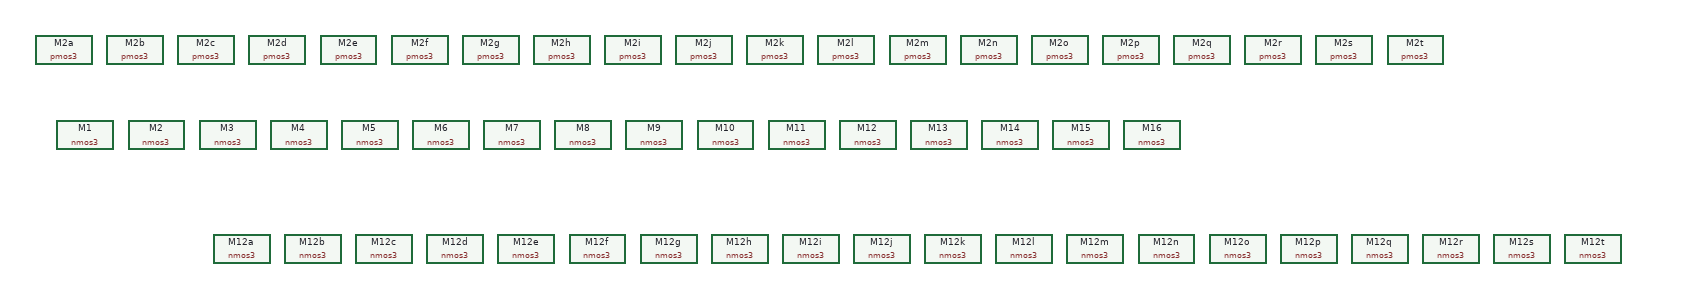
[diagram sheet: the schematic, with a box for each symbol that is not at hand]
v {xschem version=2.9.9 file_version=1.2 }
G {}
K {}
V {}
S {}
E {}
C {madvlsi/pmos3.sym} 580 -1460 1 0 {name=M2a
L=0.5
W=3
body=VDD
nf=1
mult=1
ad="'int((nf+1)/2) * W/nf * 0.29'" 
pd="'2*int((nf+1)/2) * (W/nf + 0.29)'"
as="'int((nf+2)/2) * W/nf * 0.29'" 
ps="'2*int((nf+2)/2) * (W/nf + 0.29)'"
nrd="'0.29 / W'" nrs="'0.29 / W'"
sa=0 sb=0 sd=0
model=pfet_01v8
spiceprefix=X
}
C {madvlsi/nmos3.sym} 830 -1180 1 0 {name=M12a
L=0.5
W=3
body=GND
nf=1
mult=1
ad="'int((nf+1)/2) * W/nf * 0.29'" 
pd="'2*int((nf+1)/2) * (W/nf + 0.29)'"
as="'int((nf+2)/2) * W/nf * 0.29'" 
ps="'2*int((nf+2)/2) * (W/nf + 0.29)'"
nrd="'0.29 / W'" nrs="'0.29 / W'"
sa=0 sb=0 sd=0
model=nfet_01v8
spiceprefix=X
}
C {madvlsi/nmos3.sym} 930 -1180 1 0 {name=M12b
L=0.5
W=3
body=GND
nf=1
mult=1
ad="'int((nf+1)/2) * W/nf * 0.29'" 
pd="'2*int((nf+1)/2) * (W/nf + 0.29)'"
as="'int((nf+2)/2) * W/nf * 0.29'" 
ps="'2*int((nf+2)/2) * (W/nf + 0.29)'"
nrd="'0.29 / W'" nrs="'0.29 / W'"
sa=0 sb=0 sd=0
model=nfet_01v8
spiceprefix=X
}
C {madvlsi/nmos3.sym} 1030 -1180 1 0 {name=M12c
L=0.5
W=3
body=GND
nf=1
mult=1
ad="'int((nf+1)/2) * W/nf * 0.29'" 
pd="'2*int((nf+1)/2) * (W/nf + 0.29)'"
as="'int((nf+2)/2) * W/nf * 0.29'" 
ps="'2*int((nf+2)/2) * (W/nf + 0.29)'"
nrd="'0.29 / W'" nrs="'0.29 / W'"
sa=0 sb=0 sd=0
model=nfet_01v8
spiceprefix=X
}
C {madvlsi/nmos3.sym} 1130 -1180 1 0 {name=M12d
L=0.5
W=3
body=GND
nf=1
mult=1
ad="'int((nf+1)/2) * W/nf * 0.29'" 
pd="'2*int((nf+1)/2) * (W/nf + 0.29)'"
as="'int((nf+2)/2) * W/nf * 0.29'" 
ps="'2*int((nf+2)/2) * (W/nf + 0.29)'"
nrd="'0.29 / W'" nrs="'0.29 / W'"
sa=0 sb=0 sd=0
model=nfet_01v8
spiceprefix=X
}
C {madvlsi/nmos3.sym} 1230 -1180 1 0 {name=M12e
L=0.5
W=3
body=GND
nf=1
mult=1
ad="'int((nf+1)/2) * W/nf * 0.29'" 
pd="'2*int((nf+1)/2) * (W/nf + 0.29)'"
as="'int((nf+2)/2) * W/nf * 0.29'" 
ps="'2*int((nf+2)/2) * (W/nf + 0.29)'"
nrd="'0.29 / W'" nrs="'0.29 / W'"
sa=0 sb=0 sd=0
model=nfet_01v8
spiceprefix=X
}
C {madvlsi/nmos3.sym} 1330 -1180 1 0 {name=M12f
L=0.5
W=3
body=GND
nf=1
mult=1
ad="'int((nf+1)/2) * W/nf * 0.29'" 
pd="'2*int((nf+1)/2) * (W/nf + 0.29)'"
as="'int((nf+2)/2) * W/nf * 0.29'" 
ps="'2*int((nf+2)/2) * (W/nf + 0.29)'"
nrd="'0.29 / W'" nrs="'0.29 / W'"
sa=0 sb=0 sd=0
model=nfet_01v8
spiceprefix=X
}
C {madvlsi/nmos3.sym} 1430 -1180 1 0 {name=M12g
L=0.5
W=3
body=GND
nf=1
mult=1
ad="'int((nf+1)/2) * W/nf * 0.29'" 
pd="'2*int((nf+1)/2) * (W/nf + 0.29)'"
as="'int((nf+2)/2) * W/nf * 0.29'" 
ps="'2*int((nf+2)/2) * (W/nf + 0.29)'"
nrd="'0.29 / W'" nrs="'0.29 / W'"
sa=0 sb=0 sd=0
model=nfet_01v8
spiceprefix=X
}
C {madvlsi/nmos3.sym} 1530 -1180 1 0 {name=M12h
L=0.5
W=3
body=GND
nf=1
mult=1
ad="'int((nf+1)/2) * W/nf * 0.29'" 
pd="'2*int((nf+1)/2) * (W/nf + 0.29)'"
as="'int((nf+2)/2) * W/nf * 0.29'" 
ps="'2*int((nf+2)/2) * (W/nf + 0.29)'"
nrd="'0.29 / W'" nrs="'0.29 / W'"
sa=0 sb=0 sd=0
model=nfet_01v8
spiceprefix=X
}
C {madvlsi/nmos3.sym} 1630 -1180 1 0 {name=M12i
L=0.5
W=3
body=GND
nf=1
mult=1
ad="'int((nf+1)/2) * W/nf * 0.29'" 
pd="'2*int((nf+1)/2) * (W/nf + 0.29)'"
as="'int((nf+2)/2) * W/nf * 0.29'" 
ps="'2*int((nf+2)/2) * (W/nf + 0.29)'"
nrd="'0.29 / W'" nrs="'0.29 / W'"
sa=0 sb=0 sd=0
model=nfet_01v8
spiceprefix=X
}
C {madvlsi/nmos3.sym} 1730 -1180 1 0 {name=M12j
L=0.5
W=3
body=GND
nf=1
mult=1
ad="'int((nf+1)/2) * W/nf * 0.29'" 
pd="'2*int((nf+1)/2) * (W/nf + 0.29)'"
as="'int((nf+2)/2) * W/nf * 0.29'" 
ps="'2*int((nf+2)/2) * (W/nf + 0.29)'"
nrd="'0.29 / W'" nrs="'0.29 / W'"
sa=0 sb=0 sd=0
model=nfet_01v8
spiceprefix=X
}
C {madvlsi/nmos3.sym} 1830 -1180 1 0 {name=M12k
L=0.5
W=3
body=GND
nf=1
mult=1
ad="'int((nf+1)/2) * W/nf * 0.29'" 
pd="'2*int((nf+1)/2) * (W/nf + 0.29)'"
as="'int((nf+2)/2) * W/nf * 0.29'" 
ps="'2*int((nf+2)/2) * (W/nf + 0.29)'"
nrd="'0.29 / W'" nrs="'0.29 / W'"
sa=0 sb=0 sd=0
model=nfet_01v8
spiceprefix=X
}
C {madvlsi/nmos3.sym} 1930 -1180 1 0 {name=M12l
L=0.5
W=3
body=GND
nf=1
mult=1
ad="'int((nf+1)/2) * W/nf * 0.29'" 
pd="'2*int((nf+1)/2) * (W/nf + 0.29)'"
as="'int((nf+2)/2) * W/nf * 0.29'" 
ps="'2*int((nf+2)/2) * (W/nf + 0.29)'"
nrd="'0.29 / W'" nrs="'0.29 / W'"
sa=0 sb=0 sd=0
model=nfet_01v8
spiceprefix=X
}
C {madvlsi/nmos3.sym} 2030 -1180 1 0 {name=M12m
L=0.5
W=3
body=GND
nf=1
mult=1
ad="'int((nf+1)/2) * W/nf * 0.29'" 
pd="'2*int((nf+1)/2) * (W/nf + 0.29)'"
as="'int((nf+2)/2) * W/nf * 0.29'" 
ps="'2*int((nf+2)/2) * (W/nf + 0.29)'"
nrd="'0.29 / W'" nrs="'0.29 / W'"
sa=0 sb=0 sd=0
model=nfet_01v8
spiceprefix=X
}
C {madvlsi/nmos3.sym} 2130 -1180 1 0 {name=M12n
L=0.5
W=3
body=GND
nf=1
mult=1
ad="'int((nf+1)/2) * W/nf * 0.29'" 
pd="'2*int((nf+1)/2) * (W/nf + 0.29)'"
as="'int((nf+2)/2) * W/nf * 0.29'" 
ps="'2*int((nf+2)/2) * (W/nf + 0.29)'"
nrd="'0.29 / W'" nrs="'0.29 / W'"
sa=0 sb=0 sd=0
model=nfet_01v8
spiceprefix=X
}
C {madvlsi/nmos3.sym} 2230 -1180 1 0 {name=M12o
L=0.5
W=3
body=GND
nf=1
mult=1
ad="'int((nf+1)/2) * W/nf * 0.29'" 
pd="'2*int((nf+1)/2) * (W/nf + 0.29)'"
as="'int((nf+2)/2) * W/nf * 0.29'" 
ps="'2*int((nf+2)/2) * (W/nf + 0.29)'"
nrd="'0.29 / W'" nrs="'0.29 / W'"
sa=0 sb=0 sd=0
model=nfet_01v8
spiceprefix=X
}
C {madvlsi/nmos3.sym} 2330 -1180 1 0 {name=M12p
L=0.5
W=3
body=GND
nf=1
mult=1
ad="'int((nf+1)/2) * W/nf * 0.29'" 
pd="'2*int((nf+1)/2) * (W/nf + 0.29)'"
as="'int((nf+2)/2) * W/nf * 0.29'" 
ps="'2*int((nf+2)/2) * (W/nf + 0.29)'"
nrd="'0.29 / W'" nrs="'0.29 / W'"
sa=0 sb=0 sd=0
model=nfet_01v8
spiceprefix=X
}
C {madvlsi/nmos3.sym} 2430 -1180 1 0 {name=M12q
L=0.5
W=3
body=GND
nf=1
mult=1
ad="'int((nf+1)/2) * W/nf * 0.29'" 
pd="'2*int((nf+1)/2) * (W/nf + 0.29)'"
as="'int((nf+2)/2) * W/nf * 0.29'" 
ps="'2*int((nf+2)/2) * (W/nf + 0.29)'"
nrd="'0.29 / W'" nrs="'0.29 / W'"
sa=0 sb=0 sd=0
model=nfet_01v8
spiceprefix=X
}
C {madvlsi/nmos3.sym} 2530 -1180 1 0 {name=M12r
L=0.5
W=3
body=GND
nf=1
mult=1
ad="'int((nf+1)/2) * W/nf * 0.29'" 
pd="'2*int((nf+1)/2) * (W/nf + 0.29)'"
as="'int((nf+2)/2) * W/nf * 0.29'" 
ps="'2*int((nf+2)/2) * (W/nf + 0.29)'"
nrd="'0.29 / W'" nrs="'0.29 / W'"
sa=0 sb=0 sd=0
model=nfet_01v8
spiceprefix=X
}
C {madvlsi/nmos3.sym} 2630 -1180 1 0 {name=M12s
L=0.5
W=3
body=GND
nf=1
mult=1
ad="'int((nf+1)/2) * W/nf * 0.29'" 
pd="'2*int((nf+1)/2) * (W/nf + 0.29)'"
as="'int((nf+2)/2) * W/nf * 0.29'" 
ps="'2*int((nf+2)/2) * (W/nf + 0.29)'"
nrd="'0.29 / W'" nrs="'0.29 / W'"
sa=0 sb=0 sd=0
model=nfet_01v8
spiceprefix=X
}
C {madvlsi/nmos3.sym} 2730 -1180 1 0 {name=M12t
L=0.5
W=3
body=GND
nf=1
mult=1
ad="'int((nf+1)/2) * W/nf * 0.29'" 
pd="'2*int((nf+1)/2) * (W/nf + 0.29)'"
as="'int((nf+2)/2) * W/nf * 0.29'" 
ps="'2*int((nf+2)/2) * (W/nf + 0.29)'"
nrd="'0.29 / W'" nrs="'0.29 / W'"
sa=0 sb=0 sd=0
model=nfet_01v8
spiceprefix=X
}
C {madvlsi/pmos3.sym} 680 -1460 1 0 {name=M2b
L=0.5
W=3
body=VDD
nf=1
mult=1
ad="'int((nf+1)/2) * W/nf * 0.29'" 
pd="'2*int((nf+1)/2) * (W/nf + 0.29)'"
as="'int((nf+2)/2) * W/nf * 0.29'" 
ps="'2*int((nf+2)/2) * (W/nf + 0.29)'"
nrd="'0.29 / W'" nrs="'0.29 / W'"
sa=0 sb=0 sd=0
model=pfet_01v8
spiceprefix=X
}
C {madvlsi/pmos3.sym} 780 -1460 1 0 {name=M2c
L=0.5
W=3
body=VDD
nf=1
mult=1
ad="'int((nf+1)/2) * W/nf * 0.29'" 
pd="'2*int((nf+1)/2) * (W/nf + 0.29)'"
as="'int((nf+2)/2) * W/nf * 0.29'" 
ps="'2*int((nf+2)/2) * (W/nf + 0.29)'"
nrd="'0.29 / W'" nrs="'0.29 / W'"
sa=0 sb=0 sd=0
model=pfet_01v8
spiceprefix=X
}
C {madvlsi/pmos3.sym} 880 -1460 1 0 {name=M2d
L=0.5
W=3
body=VDD
nf=1
mult=1
ad="'int((nf+1)/2) * W/nf * 0.29'" 
pd="'2*int((nf+1)/2) * (W/nf + 0.29)'"
as="'int((nf+2)/2) * W/nf * 0.29'" 
ps="'2*int((nf+2)/2) * (W/nf + 0.29)'"
nrd="'0.29 / W'" nrs="'0.29 / W'"
sa=0 sb=0 sd=0
model=pfet_01v8
spiceprefix=X
}
C {madvlsi/pmos3.sym} 980 -1460 1 0 {name=M2e
L=0.5
W=3
body=VDD
nf=1
mult=1
ad="'int((nf+1)/2) * W/nf * 0.29'" 
pd="'2*int((nf+1)/2) * (W/nf + 0.29)'"
as="'int((nf+2)/2) * W/nf * 0.29'" 
ps="'2*int((nf+2)/2) * (W/nf + 0.29)'"
nrd="'0.29 / W'" nrs="'0.29 / W'"
sa=0 sb=0 sd=0
model=pfet_01v8
spiceprefix=X
}
C {madvlsi/pmos3.sym} 1080 -1460 1 0 {name=M2f
L=0.5
W=3
body=VDD
nf=1
mult=1
ad="'int((nf+1)/2) * W/nf * 0.29'" 
pd="'2*int((nf+1)/2) * (W/nf + 0.29)'"
as="'int((nf+2)/2) * W/nf * 0.29'" 
ps="'2*int((nf+2)/2) * (W/nf + 0.29)'"
nrd="'0.29 / W'" nrs="'0.29 / W'"
sa=0 sb=0 sd=0
model=pfet_01v8
spiceprefix=X
}
C {madvlsi/pmos3.sym} 1180 -1460 1 0 {name=M2g
L=0.5
W=3
body=VDD
nf=1
mult=1
ad="'int((nf+1)/2) * W/nf * 0.29'" 
pd="'2*int((nf+1)/2) * (W/nf + 0.29)'"
as="'int((nf+2)/2) * W/nf * 0.29'" 
ps="'2*int((nf+2)/2) * (W/nf + 0.29)'"
nrd="'0.29 / W'" nrs="'0.29 / W'"
sa=0 sb=0 sd=0
model=pfet_01v8
spiceprefix=X
}
C {madvlsi/pmos3.sym} 1280 -1460 1 0 {name=M2h
L=0.5
W=3
body=VDD
nf=1
mult=1
ad="'int((nf+1)/2) * W/nf * 0.29'" 
pd="'2*int((nf+1)/2) * (W/nf + 0.29)'"
as="'int((nf+2)/2) * W/nf * 0.29'" 
ps="'2*int((nf+2)/2) * (W/nf + 0.29)'"
nrd="'0.29 / W'" nrs="'0.29 / W'"
sa=0 sb=0 sd=0
model=pfet_01v8
spiceprefix=X
}
C {madvlsi/pmos3.sym} 1380 -1460 1 0 {name=M2i
L=0.5
W=3
body=VDD
nf=1
mult=1
ad="'int((nf+1)/2) * W/nf * 0.29'" 
pd="'2*int((nf+1)/2) * (W/nf + 0.29)'"
as="'int((nf+2)/2) * W/nf * 0.29'" 
ps="'2*int((nf+2)/2) * (W/nf + 0.29)'"
nrd="'0.29 / W'" nrs="'0.29 / W'"
sa=0 sb=0 sd=0
model=pfet_01v8
spiceprefix=X
}
C {madvlsi/pmos3.sym} 1480 -1460 1 0 {name=M2j
L=0.5
W=3
body=VDD
nf=1
mult=1
ad="'int((nf+1)/2) * W/nf * 0.29'" 
pd="'2*int((nf+1)/2) * (W/nf + 0.29)'"
as="'int((nf+2)/2) * W/nf * 0.29'" 
ps="'2*int((nf+2)/2) * (W/nf + 0.29)'"
nrd="'0.29 / W'" nrs="'0.29 / W'"
sa=0 sb=0 sd=0
model=pfet_01v8
spiceprefix=X
}
C {madvlsi/pmos3.sym} 1580 -1460 1 0 {name=M2k
L=0.5
W=3
body=VDD
nf=1
mult=1
ad="'int((nf+1)/2) * W/nf * 0.29'" 
pd="'2*int((nf+1)/2) * (W/nf + 0.29)'"
as="'int((nf+2)/2) * W/nf * 0.29'" 
ps="'2*int((nf+2)/2) * (W/nf + 0.29)'"
nrd="'0.29 / W'" nrs="'0.29 / W'"
sa=0 sb=0 sd=0
model=pfet_01v8
spiceprefix=X
}
C {madvlsi/pmos3.sym} 1680 -1460 1 0 {name=M2l
L=0.5
W=3
body=VDD
nf=1
mult=1
ad="'int((nf+1)/2) * W/nf * 0.29'" 
pd="'2*int((nf+1)/2) * (W/nf + 0.29)'"
as="'int((nf+2)/2) * W/nf * 0.29'" 
ps="'2*int((nf+2)/2) * (W/nf + 0.29)'"
nrd="'0.29 / W'" nrs="'0.29 / W'"
sa=0 sb=0 sd=0
model=pfet_01v8
spiceprefix=X
}
C {madvlsi/pmos3.sym} 1780 -1460 1 0 {name=M2m
L=0.5
W=3
body=VDD
nf=1
mult=1
ad="'int((nf+1)/2) * W/nf * 0.29'" 
pd="'2*int((nf+1)/2) * (W/nf + 0.29)'"
as="'int((nf+2)/2) * W/nf * 0.29'" 
ps="'2*int((nf+2)/2) * (W/nf + 0.29)'"
nrd="'0.29 / W'" nrs="'0.29 / W'"
sa=0 sb=0 sd=0
model=pfet_01v8
spiceprefix=X
}
C {madvlsi/pmos3.sym} 1880 -1460 1 0 {name=M2n
L=0.5
W=3
body=VDD
nf=1
mult=1
ad="'int((nf+1)/2) * W/nf * 0.29'" 
pd="'2*int((nf+1)/2) * (W/nf + 0.29)'"
as="'int((nf+2)/2) * W/nf * 0.29'" 
ps="'2*int((nf+2)/2) * (W/nf + 0.29)'"
nrd="'0.29 / W'" nrs="'0.29 / W'"
sa=0 sb=0 sd=0
model=pfet_01v8
spiceprefix=X
}
C {madvlsi/pmos3.sym} 1980 -1460 1 0 {name=M2o
L=0.5
W=3
body=VDD
nf=1
mult=1
ad="'int((nf+1)/2) * W/nf * 0.29'" 
pd="'2*int((nf+1)/2) * (W/nf + 0.29)'"
as="'int((nf+2)/2) * W/nf * 0.29'" 
ps="'2*int((nf+2)/2) * (W/nf + 0.29)'"
nrd="'0.29 / W'" nrs="'0.29 / W'"
sa=0 sb=0 sd=0
model=pfet_01v8
spiceprefix=X
}
C {madvlsi/pmos3.sym} 2080 -1460 1 0 {name=M2p
L=0.5
W=3
body=VDD
nf=1
mult=1
ad="'int((nf+1)/2) * W/nf * 0.29'" 
pd="'2*int((nf+1)/2) * (W/nf + 0.29)'"
as="'int((nf+2)/2) * W/nf * 0.29'" 
ps="'2*int((nf+2)/2) * (W/nf + 0.29)'"
nrd="'0.29 / W'" nrs="'0.29 / W'"
sa=0 sb=0 sd=0
model=pfet_01v8
spiceprefix=X
}
C {madvlsi/pmos3.sym} 2180 -1460 1 0 {name=M2q
L=0.5
W=3
body=VDD
nf=1
mult=1
ad="'int((nf+1)/2) * W/nf * 0.29'" 
pd="'2*int((nf+1)/2) * (W/nf + 0.29)'"
as="'int((nf+2)/2) * W/nf * 0.29'" 
ps="'2*int((nf+2)/2) * (W/nf + 0.29)'"
nrd="'0.29 / W'" nrs="'0.29 / W'"
sa=0 sb=0 sd=0
model=pfet_01v8
spiceprefix=X
}
C {madvlsi/pmos3.sym} 2280 -1460 1 0 {name=M2r
L=0.5
W=3
body=VDD
nf=1
mult=1
ad="'int((nf+1)/2) * W/nf * 0.29'" 
pd="'2*int((nf+1)/2) * (W/nf + 0.29)'"
as="'int((nf+2)/2) * W/nf * 0.29'" 
ps="'2*int((nf+2)/2) * (W/nf + 0.29)'"
nrd="'0.29 / W'" nrs="'0.29 / W'"
sa=0 sb=0 sd=0
model=pfet_01v8
spiceprefix=X
}
C {madvlsi/pmos3.sym} 2380 -1460 1 0 {name=M2s
L=0.5
W=3
body=VDD
nf=1
mult=1
ad="'int((nf+1)/2) * W/nf * 0.29'" 
pd="'2*int((nf+1)/2) * (W/nf + 0.29)'"
as="'int((nf+2)/2) * W/nf * 0.29'" 
ps="'2*int((nf+2)/2) * (W/nf + 0.29)'"
nrd="'0.29 / W'" nrs="'0.29 / W'"
sa=0 sb=0 sd=0
model=pfet_01v8
spiceprefix=X
}
C {madvlsi/pmos3.sym} 2480 -1460 1 0 {name=M2t
L=0.5
W=3
body=VDD
nf=1
mult=1
ad="'int((nf+1)/2) * W/nf * 0.29'" 
pd="'2*int((nf+1)/2) * (W/nf + 0.29)'"
as="'int((nf+2)/2) * W/nf * 0.29'" 
ps="'2*int((nf+2)/2) * (W/nf + 0.29)'"
nrd="'0.29 / W'" nrs="'0.29 / W'"
sa=0 sb=0 sd=0
model=pfet_01v8
spiceprefix=X
}
C {madvlsi/nmos3.sym} 610 -1340 1 0 {name=M1
L=0.5
W=3
body=GND
nf=1
mult=1
ad="'int((nf+1)/2) * W/nf * 0.29'" 
pd="'2*int((nf+1)/2) * (W/nf + 0.29)'"
as="'int((nf+2)/2) * W/nf * 0.29'" 
ps="'2*int((nf+2)/2) * (W/nf + 0.29)'"
nrd="'0.29 / W'" nrs="'0.29 / W'"
sa=0 sb=0 sd=0
model=nfet_01v8
spiceprefix=X
}
C {madvlsi/nmos3.sym} 710 -1340 1 0 {name=M2
L=0.5
W=3
body=GND
nf=1
mult=1
ad="'int((nf+1)/2) * W/nf * 0.29'" 
pd="'2*int((nf+1)/2) * (W/nf + 0.29)'"
as="'int((nf+2)/2) * W/nf * 0.29'" 
ps="'2*int((nf+2)/2) * (W/nf + 0.29)'"
nrd="'0.29 / W'" nrs="'0.29 / W'"
sa=0 sb=0 sd=0
model=nfet_01v8
spiceprefix=X
}
C {madvlsi/nmos3.sym} 810 -1340 1 0 {name=M3
L=0.5
W=3
body=GND
nf=1
mult=1
ad="'int((nf+1)/2) * W/nf * 0.29'" 
pd="'2*int((nf+1)/2) * (W/nf + 0.29)'"
as="'int((nf+2)/2) * W/nf * 0.29'" 
ps="'2*int((nf+2)/2) * (W/nf + 0.29)'"
nrd="'0.29 / W'" nrs="'0.29 / W'"
sa=0 sb=0 sd=0
model=nfet_01v8
spiceprefix=X
}
C {madvlsi/nmos3.sym} 910 -1340 1 0 {name=M4
L=0.5
W=3
body=GND
nf=1
mult=1
ad="'int((nf+1)/2) * W/nf * 0.29'" 
pd="'2*int((nf+1)/2) * (W/nf + 0.29)'"
as="'int((nf+2)/2) * W/nf * 0.29'" 
ps="'2*int((nf+2)/2) * (W/nf + 0.29)'"
nrd="'0.29 / W'" nrs="'0.29 / W'"
sa=0 sb=0 sd=0
model=nfet_01v8
spiceprefix=X
}
C {madvlsi/nmos3.sym} 1010 -1340 1 0 {name=M5
L=0.5
W=3
body=GND
nf=1
mult=1
ad="'int((nf+1)/2) * W/nf * 0.29'" 
pd="'2*int((nf+1)/2) * (W/nf + 0.29)'"
as="'int((nf+2)/2) * W/nf * 0.29'" 
ps="'2*int((nf+2)/2) * (W/nf + 0.29)'"
nrd="'0.29 / W'" nrs="'0.29 / W'"
sa=0 sb=0 sd=0
model=nfet_01v8
spiceprefix=X
}
C {madvlsi/nmos3.sym} 1110 -1340 1 0 {name=M6
L=0.5
W=3
body=GND
nf=1
mult=1
ad="'int((nf+1)/2) * W/nf * 0.29'" 
pd="'2*int((nf+1)/2) * (W/nf + 0.29)'"
as="'int((nf+2)/2) * W/nf * 0.29'" 
ps="'2*int((nf+2)/2) * (W/nf + 0.29)'"
nrd="'0.29 / W'" nrs="'0.29 / W'"
sa=0 sb=0 sd=0
model=nfet_01v8
spiceprefix=X
}
C {madvlsi/nmos3.sym} 1210 -1340 1 0 {name=M7
L=0.5
W=3
body=GND
nf=1
mult=1
ad="'int((nf+1)/2) * W/nf * 0.29'" 
pd="'2*int((nf+1)/2) * (W/nf + 0.29)'"
as="'int((nf+2)/2) * W/nf * 0.29'" 
ps="'2*int((nf+2)/2) * (W/nf + 0.29)'"
nrd="'0.29 / W'" nrs="'0.29 / W'"
sa=0 sb=0 sd=0
model=nfet_01v8
spiceprefix=X
}
C {madvlsi/nmos3.sym} 1310 -1340 1 0 {name=M8
L=0.5
W=3
body=GND
nf=1
mult=1
ad="'int((nf+1)/2) * W/nf * 0.29'" 
pd="'2*int((nf+1)/2) * (W/nf + 0.29)'"
as="'int((nf+2)/2) * W/nf * 0.29'" 
ps="'2*int((nf+2)/2) * (W/nf + 0.29)'"
nrd="'0.29 / W'" nrs="'0.29 / W'"
sa=0 sb=0 sd=0
model=nfet_01v8
spiceprefix=X
}
C {madvlsi/nmos3.sym} 1410 -1340 1 0 {name=M9
L=0.5
W=3
body=GND
nf=1
mult=1
ad="'int((nf+1)/2) * W/nf * 0.29'" 
pd="'2*int((nf+1)/2) * (W/nf + 0.29)'"
as="'int((nf+2)/2) * W/nf * 0.29'" 
ps="'2*int((nf+2)/2) * (W/nf + 0.29)'"
nrd="'0.29 / W'" nrs="'0.29 / W'"
sa=0 sb=0 sd=0
model=nfet_01v8
spiceprefix=X
}
C {madvlsi/nmos3.sym} 1510 -1340 1 0 {name=M10
L=0.5
W=3
body=GND
nf=1
mult=1
ad="'int((nf+1)/2) * W/nf * 0.29'" 
pd="'2*int((nf+1)/2) * (W/nf + 0.29)'"
as="'int((nf+2)/2) * W/nf * 0.29'" 
ps="'2*int((nf+2)/2) * (W/nf + 0.29)'"
nrd="'0.29 / W'" nrs="'0.29 / W'"
sa=0 sb=0 sd=0
model=nfet_01v8
spiceprefix=X
}
C {madvlsi/nmos3.sym} 1610 -1340 1 0 {name=M11
L=0.5
W=3
body=GND
nf=1
mult=1
ad="'int((nf+1)/2) * W/nf * 0.29'" 
pd="'2*int((nf+1)/2) * (W/nf + 0.29)'"
as="'int((nf+2)/2) * W/nf * 0.29'" 
ps="'2*int((nf+2)/2) * (W/nf + 0.29)'"
nrd="'0.29 / W'" nrs="'0.29 / W'"
sa=0 sb=0 sd=0
model=nfet_01v8
spiceprefix=X
}
C {madvlsi/nmos3.sym} 1710 -1340 1 0 {name=M12
L=0.5
W=3
body=GND
nf=1
mult=1
ad="'int((nf+1)/2) * W/nf * 0.29'" 
pd="'2*int((nf+1)/2) * (W/nf + 0.29)'"
as="'int((nf+2)/2) * W/nf * 0.29'" 
ps="'2*int((nf+2)/2) * (W/nf + 0.29)'"
nrd="'0.29 / W'" nrs="'0.29 / W'"
sa=0 sb=0 sd=0
model=nfet_01v8
spiceprefix=X
}
C {madvlsi/nmos3.sym} 1810 -1340 1 0 {name=M13
L=0.5
W=3
body=GND
nf=1
mult=1
ad="'int((nf+1)/2) * W/nf * 0.29'" 
pd="'2*int((nf+1)/2) * (W/nf + 0.29)'"
as="'int((nf+2)/2) * W/nf * 0.29'" 
ps="'2*int((nf+2)/2) * (W/nf + 0.29)'"
nrd="'0.29 / W'" nrs="'0.29 / W'"
sa=0 sb=0 sd=0
model=nfet_01v8
spiceprefix=X
}
C {madvlsi/nmos3.sym} 1910 -1340 1 0 {name=M14
L=0.5
W=3
body=GND
nf=1
mult=1
ad="'int((nf+1)/2) * W/nf * 0.29'" 
pd="'2*int((nf+1)/2) * (W/nf + 0.29)'"
as="'int((nf+2)/2) * W/nf * 0.29'" 
ps="'2*int((nf+2)/2) * (W/nf + 0.29)'"
nrd="'0.29 / W'" nrs="'0.29 / W'"
sa=0 sb=0 sd=0
model=nfet_01v8
spiceprefix=X
}
C {madvlsi/nmos3.sym} 2010 -1340 1 0 {name=M15
L=0.5
W=3
body=GND
nf=1
mult=1
ad="'int((nf+1)/2) * W/nf * 0.29'" 
pd="'2*int((nf+1)/2) * (W/nf + 0.29)'"
as="'int((nf+2)/2) * W/nf * 0.29'" 
ps="'2*int((nf+2)/2) * (W/nf + 0.29)'"
nrd="'0.29 / W'" nrs="'0.29 / W'"
sa=0 sb=0 sd=0
model=nfet_01v8
spiceprefix=X
}
C {madvlsi/nmos3.sym} 2110 -1340 1 0 {name=M16
L=0.5
W=3
body=GND
nf=1
mult=1
ad="'int((nf+1)/2) * W/nf * 0.29'" 
pd="'2*int((nf+1)/2) * (W/nf + 0.29)'"
as="'int((nf+2)/2) * W/nf * 0.29'" 
ps="'2*int((nf+2)/2) * (W/nf + 0.29)'"
nrd="'0.29 / W'" nrs="'0.29 / W'"
sa=0 sb=0 sd=0
model=nfet_01v8
spiceprefix=X
}
